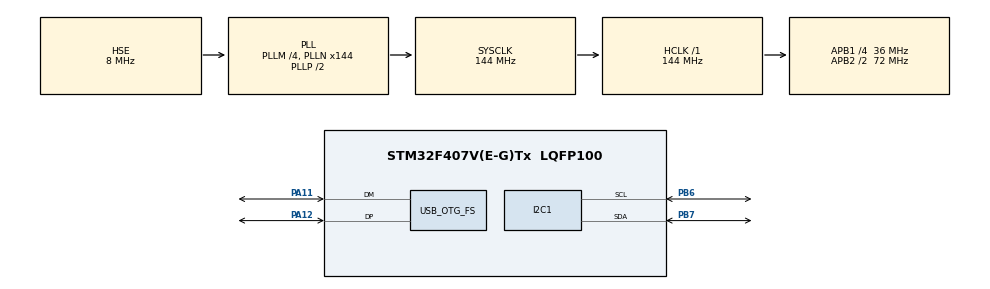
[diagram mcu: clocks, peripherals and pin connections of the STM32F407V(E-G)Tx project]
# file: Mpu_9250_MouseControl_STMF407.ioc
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Mcu.Family=STM32F4
Mcu.Name=STM32F407V(E-G)Tx
Mcu.Package=LQFP100
NVIC.OTG_FS_IRQn=true\:0\:0\:false\:false\:true\:false
NVIC.PriorityGroup=NVIC_PRIORITYGROUP_4
NVIC.TIM1_UP_TIM10_IRQn=true\:0\:0\:false\:false\:true\:true
PA11.Mode=Device_Only
PA11.Signal=USB_OTG_FS_DM
PA12.Mode=Device_Only
PA12.Signal=USB_OTG_FS_DP
PB6.Mode=I2C
PB6.Signal=I2C1_SCL
PB7.Mode=I2C
PB7.Signal=I2C1_SDA
PH0-OSC_IN.Mode=HSE-External-Oscillator
PH0-OSC_IN.Signal=RCC_OSC_IN
PH1-OSC_OUT.Mode=HSE-External-Oscillator
PH1-OSC_OUT.Signal=RCC_OSC_OUT
ProjectManager.HeapSize=0x200
ProjectManager.StackSize=0x400
ProjectManager.TargetToolchain=MDK-ARM V5
RCC.48MHZClocksFreq_Value=48000000
RCC.AHBFreq_Value=144000000
RCC.APB1CLKDivider=RCC_HCLK_DIV4
RCC.APB1Freq_Value=36000000
RCC.APB1TimFreq_Value=72000000
RCC.APB2CLKDivider=RCC_HCLK_DIV2
RCC.APB2Freq_Value=72000000
RCC.APB2TimFreq_Value=144000000
RCC.CortexFreq_Value=144000000
RCC.HCLKFreq_Value=144000000
RCC.HSE_VALUE=8000000
RCC.HSI_VALUE=16000000
RCC.LSE_VALUE=32768
RCC.PLLM=4
RCC.PLLN=144
RCC.PLLQ=6
RCC.SYSCLKFreq_VALUE=144000000
RCC.SYSCLKSource=RCC_SYSCLKSOURCE_PLLCLK
RCC.VCOOutputFreq_Value=288000000
TIM1.Period=45
TIM1.Prescaler=32000
TIM1.TIM_MasterOutputTrigger=TIM_TRGO_UPDATE
TIM2.Period=20
TIM2.Prescaler=36000
TIM2.TIM_MasterOutputTrigger=TIM_TRGO_UPDATE
USB_DEVICE.CLASS_NAME_FS=HID
USB_DEVICE.VirtualMode-HID_FS=Hid
USB_DEVICE.VirtualModeFS=Hid_FS
USB_OTG_FS.VirtualMode=Device_Only
VP_TIM1_VS_ClockSourceINT.Mode=Internal
VP_TIM2_VS_ClockSourceINT.Mode=Internal
VP_USB_DEVICE_VS_USB_DEVICE_HID_FS.Mode=HID_FS
board=Mpu_9250_MouseControl_STMF407

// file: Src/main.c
/**
  ******************************************************************************
  * @file           : main.c
  * @brief          : Main program body
  ******************************************************************************
  * This notice applies to any and all portions of this file
  * that are not between comment pairs USER CODE BEGIN and
  * USER CODE END. Other portions of this file, whether
  * inserted by the user or by software development tools
  * are owned by their respective copyright owners.
  *
  * Copyright (c) 2018 STMicroelectronics International N.V.
  * All rights reserved.
  *
  * Redistribution and use in source and binary forms, with or without
  * modification, are permitted, provided that the following conditions are met:
  *
  * 1. Redistribution of source code must retain the above copyright notice,
  *    this list of conditions and the following disclaimer.
  * 2. Redistributions in binary form must reproduce the above copyright notice,
  *    this list of conditions and the following disclaimer in the documentation
  *    and/or other materials provided with the distribution.
  * 3. Neither the name of STMicroelectronics nor the names of other
  *    contributors to this software may be used to endorse or promote products
  *    derived from this software without specific written permission.
  * 4. This software, including modifications and/or derivative works of this
  *    software, must execute solely and exclusively on microcontroller or
  *    microprocessor devices manufactured by or for STMicroelectronics.
  * 5. Redistribution and use of this software other than as permitted under
  *    this license is void and will automatically terminate your rights under
  *    this license.
  *
  * THIS SOFTWARE IS PROVIDED BY STMICROELECTRONICS AND CONTRIBUTORS "AS IS"
  * AND ANY EXPRESS, IMPLIED OR STATUTORY WARRANTIES, INCLUDING, BUT NOT
  * LIMITED TO, THE IMPLIED WARRANTIES OF MERCHANTABILITY, FITNESS FOR A
  * PARTICULAR PURPOSE AND NON-INFRINGEMENT OF THIRD PARTY INTELLECTUAL PROPERTY
  * RIGHTS ARE DISCLAIMED TO THE FULLEST EXTENT PERMITTED BY LAW. IN NO EVENT
  * SHALL STMICROELECTRONICS OR CONTRIBUTORS BE LIABLE FOR ANY DIRECT, INDIRECT,
  * INCIDENTAL, SPECIAL, EXEMPLARY, OR CONSEQUENTIAL DAMAGES (INCLUDING, BUT NOT
  * LIMITED TO, PROCUREMENT OF SUBSTITUTE GOODS OR SERVICES; LOSS OF USE, DATA,
  * OR PROFITS; OR BUSINESS INTERRUPTION) HOWEVER CAUSED AND ON ANY THEORY OF
  * LIABILITY, WHETHER IN CONTRACT, STRICT LIABILITY, OR TORT (INCLUDING
  * NEGLIGENCE OR OTHERWISE) ARISING IN ANY WAY OUT OF THE USE OF THIS SOFTWARE,
  * EVEN IF ADVISED OF THE POSSIBILITY OF SUCH DAMAGE.
  *
  ******************************************************************************
  */
#include "main.h"
#include "stm32f4xx_hal.h"
#include "usb_device.h"

/* USER CODE BEGIN Includes */
#include "MPU6050.h"
#include "usbd_hid.h"
/* USER CODE END Includes */

I2C_HandleTypeDef hi2c1;

TIM_HandleTypeDef htim1;
TIM_HandleTypeDef htim2;
/* USER CODE BEGIN PV */
/* Private variables ---------------------------------------------------------*/
MPU6050_GYROResult    IntGyroData;
MPU6050_ACCResult     IntAccData;
MPU6050_MAGNETResult  IntMagnetData;
MPU6050_StatusReg     Status;
/* USER CODE END PV */

void SystemClock_Config(void);
static void MX_GPIO_Init(void);
static void MX_I2C1_Init(void);
static void MX_TIM1_Init(void);
static void MX_TIM2_Init(void);

/* USER CODE BEGIN PFP */
/* Private function prototypes -----------------------------------------------*/

/* USER CODE END PFP */

int main(void)
{

  /* MCU Configuration----------------------------------------------------------*/

  /* Reset of all peripherals, Initializes the Flash interface and the Systick. */
  HAL_Init();

  /* Configure the system clock */
  SystemClock_Config();

  /* Initialize all configured peripherals */
  MX_GPIO_Init();
  MX_USB_DEVICE_Init();
  MX_I2C1_Init();
  MX_TIM1_Init();
  MX_TIM2_Init();
  HAL_Delay(100);
  /* USER CODE BEGIN 2 */
  while(Initialize() != HAL_OK) {}

  HAL_TIM_Base_Start_IT(&htim1);
	__HAL_TIM_ENABLE_IT(&htim1, TIM_IT_UPDATE);
  /* USER CODE END 2 */

  /* Infinite loop */
  while (1)
  {

  }

}

void SystemClock_Config(void)
{

  RCC_OscInitTypeDef RCC_OscInitStruct;
  RCC_ClkInitTypeDef RCC_ClkInitStruct;

    /**Configure the main internal regulator output voltage
    */
  __HAL_RCC_PWR_CLK_ENABLE();

  __HAL_PWR_VOLTAGESCALING_CONFIG(PWR_REGULATOR_VOLTAGE_SCALE1);

    /**Initializes the CPU, AHB and APB busses clocks
    */
  RCC_OscInitStruct.OscillatorType = RCC_OSCILLATORTYPE_HSE;
  RCC_OscInitStruct.HSEState = RCC_HSE_ON;
  RCC_OscInitStruct.PLL.PLLState = RCC_PLL_ON;
  RCC_OscInitStruct.PLL.PLLSource = RCC_PLLSOURCE_HSE;
  RCC_OscInitStruct.PLL.PLLM = 4;
  RCC_OscInitStruct.PLL.PLLN = 144;
  RCC_OscInitStruct.PLL.PLLP = RCC_PLLP_DIV2;
  RCC_OscInitStruct.PLL.PLLQ = 6;
  if (HAL_RCC_OscConfig(&RCC_OscInitStruct) != HAL_OK)
  {
    _Error_Handler(__FILE__, __LINE__);
  }

    /**Initializes the CPU, AHB and APB busses clocks
    */
  RCC_ClkInitStruct.ClockType = RCC_CLOCKTYPE_HCLK|RCC_CLOCKTYPE_SYSCLK
                              |RCC_CLOCKTYPE_PCLK1|RCC_CLOCKTYPE_PCLK2;
  RCC_ClkInitStruct.SYSCLKSource = RCC_SYSCLKSOURCE_PLLCLK;
  RCC_ClkInitStruct.AHBCLKDivider = RCC_SYSCLK_DIV1;
  RCC_ClkInitStruct.APB1CLKDivider = RCC_HCLK_DIV4;
  RCC_ClkInitStruct.APB2CLKDivider = RCC_HCLK_DIV2;

  if (HAL_RCC_ClockConfig(&RCC_ClkInitStruct, FLASH_LATENCY_4) != HAL_OK)
  {
    _Error_Handler(__FILE__, __LINE__);
  }

    /**Configure the Systick interrupt time
    */
  HAL_SYSTICK_Config(HAL_RCC_GetHCLKFreq()/1000);

    /**Configure the Systick
    */
  HAL_SYSTICK_CLKSourceConfig(SYSTICK_CLKSOURCE_HCLK);

  /* SysTick_IRQn interrupt configuration */
  HAL_NVIC_SetPriority(SysTick_IRQn, 0, 0);
}

/* I2C1 init function */
static void MX_I2C1_Init(void)
{

  hi2c1.Instance = I2C1;
  hi2c1.Init.ClockSpeed = 100000;
  hi2c1.Init.DutyCycle = I2C_DUTYCYCLE_2;
  hi2c1.Init.OwnAddress1 = 0;
  hi2c1.Init.AddressingMode = I2C_ADDRESSINGMODE_7BIT;
  hi2c1.Init.DualAddressMode = I2C_DUALADDRESS_DISABLE;
  hi2c1.Init.OwnAddress2 = 0;
  hi2c1.Init.GeneralCallMode = I2C_GENERALCALL_DISABLE;
  hi2c1.Init.NoStretchMode = I2C_NOSTRETCH_DISABLE;
  if (HAL_I2C_Init(&hi2c1) != HAL_OK)
  {
    _Error_Handler(__FILE__, __LINE__);
  }

}

/* TIM1 init function */
static void MX_TIM1_Init(void)
{

  TIM_ClockConfigTypeDef sClockSourceConfig;
  TIM_MasterConfigTypeDef sMasterConfig;

  htim1.Instance = TIM1;
  htim1.Init.Prescaler = 8000;
  htim1.Init.CounterMode = TIM_COUNTERMODE_UP;
  htim1.Init.Period = 90;
  htim1.Init.ClockDivision = TIM_CLOCKDIVISION_DIV1;
  htim1.Init.RepetitionCounter = 0;
  if (HAL_TIM_Base_Init(&htim1) != HAL_OK)
  {
    _Error_Handler(__FILE__, __LINE__);
  }

  sClockSourceConfig.ClockSource = TIM_CLOCKSOURCE_INTERNAL;
  if (HAL_TIM_ConfigClockSource(&htim1, &sClockSourceConfig) != HAL_OK)
  {
    _Error_Handler(__FILE__, __LINE__);
  }

  sMasterConfig.MasterOutputTrigger = TIM_TRGO_UPDATE;
  sMasterConfig.MasterSlaveMode = TIM_MASTERSLAVEMODE_DISABLE;
  if (HAL_TIMEx_MasterConfigSynchronization(&htim1, &sMasterConfig) != HAL_OK)
  {
    _Error_Handler(__FILE__, __LINE__);
  }

}

/* TIM2 init function */
static void MX_TIM2_Init(void)
{

  TIM_ClockConfigTypeDef sClockSourceConfig;
  TIM_MasterConfigTypeDef sMasterConfig;

  htim2.Instance = TIM2;
  htim2.Init.Prescaler = 36000;
  htim2.Init.CounterMode = TIM_COUNTERMODE_UP;
  htim2.Init.Period = 20;
  htim2.Init.ClockDivision = TIM_CLOCKDIVISION_DIV1;
  if (HAL_TIM_Base_Init(&htim2) != HAL_OK)
  {
    _Error_Handler(__FILE__, __LINE__);
  }

  sClockSourceConfig.ClockSource = TIM_CLOCKSOURCE_INTERNAL;
  if (HAL_TIM_ConfigClockSource(&htim2, &sClockSourceConfig) != HAL_OK)
  {
    _Error_Handler(__FILE__, __LINE__);
  }

  sMasterConfig.MasterOutputTrigger = TIM_TRGO_UPDATE;
  sMasterConfig.MasterSlaveMode = TIM_MASTERSLAVEMODE_DISABLE;
  if (HAL_TIMEx_MasterConfigSynchronization(&htim2, &sMasterConfig) != HAL_OK)
  {
    _Error_Handler(__FILE__, __LINE__);
  }

}

/** Configure pins as
        * Analog
        * Input
        * Output
        * EVENT_OUT
        * EXTI
*/
static void MX_GPIO_Init(void)
{

  /* GPIO Ports Clock Enable */
  __HAL_RCC_GPIOH_CLK_ENABLE();
  __HAL_RCC_GPIOA_CLK_ENABLE();
  __HAL_RCC_GPIOB_CLK_ENABLE();

  GPIO_InitTypeDef GPIO_InitStruct;

  /* GPIO Ports Clock Enable */
  __HAL_RCC_GPIOD_CLK_ENABLE();
  __HAL_RCC_GPIOE_CLK_ENABLE();

  /*Configure GPIO pin Output Level */
  HAL_GPIO_WritePin(GPIOE, GPIO_PIN_0, GPIO_PIN_RESET);

  /*Configure GPIO pin : PD15 */
  GPIO_InitStruct.Pin = GPIO_PIN_15;
  GPIO_InitStruct.Mode = GPIO_MODE_INPUT;
  GPIO_InitStruct.Pull = GPIO_NOPULL;
  HAL_GPIO_Init(GPIOD, &GPIO_InitStruct);

  /*Configure GPIO pin : PE0 */
  GPIO_InitStruct.Pin = GPIO_PIN_0;
  GPIO_InitStruct.Mode = GPIO_MODE_OUTPUT_PP;
  GPIO_InitStruct.Pull = GPIO_NOPULL;
  GPIO_InitStruct.Speed = GPIO_SPEED_FREQ_LOW;
  HAL_GPIO_Init(GPIOE, &GPIO_InitStruct);
}

void _Error_Handler(char *file, int line)
{
  while(1)
  {
  }
}

/************************ (C) COPYRIGHT STMicroelectronics *****END OF FILE****/
